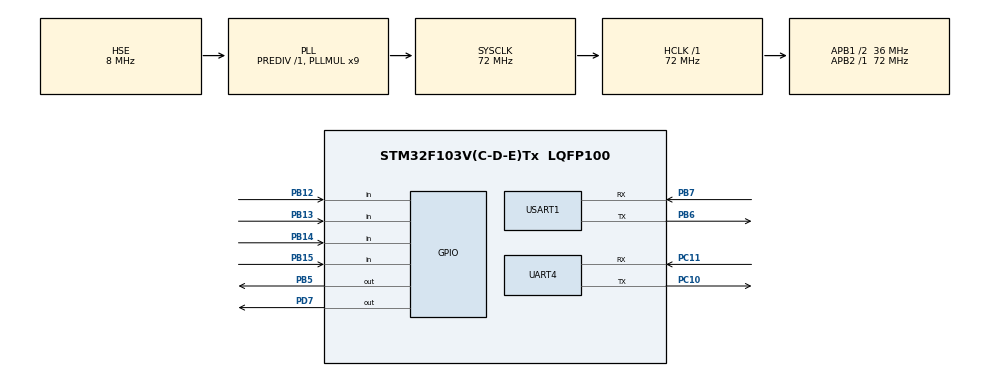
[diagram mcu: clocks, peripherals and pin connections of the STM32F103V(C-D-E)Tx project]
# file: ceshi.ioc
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Dma.Request0=USART1_RX
Dma.Request1=UART4_RX
Dma.UART4_RX.1.Direction=DMA_PERIPH_TO_MEMORY
Dma.UART4_RX.1.Instance=DMA2_Channel3
Dma.UART4_RX.1.MemDataAlignment=DMA_MDATAALIGN_BYTE
Dma.UART4_RX.1.MemInc=DMA_MINC_ENABLE
Dma.UART4_RX.1.Mode=DMA_NORMAL
Dma.UART4_RX.1.PeriphDataAlignment=DMA_PDATAALIGN_BYTE
Dma.UART4_RX.1.PeriphInc=DMA_PINC_DISABLE
Dma.UART4_RX.1.Priority=DMA_PRIORITY_LOW
Dma.USART1_RX.0.Direction=DMA_PERIPH_TO_MEMORY
Dma.USART1_RX.0.Instance=DMA1_Channel5
Dma.USART1_RX.0.MemDataAlignment=DMA_MDATAALIGN_BYTE
Dma.USART1_RX.0.MemInc=DMA_MINC_ENABLE
Dma.USART1_RX.0.Mode=DMA_NORMAL
Dma.USART1_RX.0.PeriphDataAlignment=DMA_PDATAALIGN_BYTE
Dma.USART1_RX.0.PeriphInc=DMA_PINC_DISABLE
Dma.USART1_RX.0.Priority=DMA_PRIORITY_LOW
Mcu.Family=STM32F1
Mcu.Name=STM32F103V(C-D-E)Tx
Mcu.Package=LQFP100
NVIC.DMA1_Channel5_IRQn=true\:2\:1\:true\:false\:true\:false
NVIC.DMA2_Channel3_IRQn=true\:2\:2\:true\:false\:true\:false
NVIC.PriorityGroup=NVIC_PRIORITYGROUP_2
NVIC.RCC_IRQn=true\:0\:0\:false\:false\:true\:true
NVIC.TIM6_IRQn=true\:1\:2\:true\:false\:true\:true
NVIC.TIM7_IRQn=true\:1\:1\:true\:false\:true\:true
NVIC.UART4_IRQn=true\:3\:3\:true\:false\:true\:true
NVIC.USART1_IRQn=true\:3\:2\:true\:false\:true\:true
OSC_IN.Mode=HSE-External-Oscillator
OSC_IN.Signal=RCC_OSC_IN
OSC_OUT.Mode=HSE-External-Oscillator
OSC_OUT.Signal=RCC_OSC_OUT
PB12.Signal=GPIO_Input
PB13.Signal=GPIO_Input
PB14.Signal=GPIO_Input
PB15.Signal=GPIO_Input
PB5.Signal=GPIO_Output
PB6.Mode=Asynchronous
PB6.Signal=USART1_TX
PB7.Mode=Asynchronous
PB7.Signal=USART1_RX
PC10.Mode=Asynchronous
PC10.Signal=UART4_TX
PC11.Mode=Asynchronous
PC11.Signal=UART4_RX
PD7.Signal=GPIO_Output
ProjectManager.HeapSize=0x200
ProjectManager.StackSize=0x400
ProjectManager.TargetToolchain=EWARM
RCC.AHBFreq_Value=72000000
RCC.APB1CLKDivider=RCC_HCLK_DIV2
RCC.APB1Freq_Value=36000000
RCC.APB1TimFreq_Value=72000000
RCC.APB2Freq_Value=72000000
RCC.APB2TimFreq_Value=72000000
RCC.HCLKFreq_Value=72000000
RCC.PLLMUL=RCC_PLL_MUL9
RCC.PLLSourceVirtual=RCC_PLLSOURCE_HSE
RCC.SYSCLKFreq_VALUE=72000000
RCC.SYSCLKSource=RCC_SYSCLKSOURCE_PLLCLK
RCC.USBFreq_Value=72000000
UART4.Parity=PARITY_EVEN
UART4.VirtualMode=Asynchronous
UART4.WordLength=WORDLENGTH_9B
USART1.Parity=PARITY_EVEN
USART1.VirtualMode=VM_ASYNC
USART1.WordLength=WORDLENGTH_9B
VP_SYS_VS_ND.Mode=No_Debug
VP_TIM6_VS_ClockSourceINT.Mode=Enable_Timer
VP_TIM7_VS_ClockSourceINT.Mode=Enable_Timer
board=custom

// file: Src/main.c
/**
  ******************************************************************************
//划分一页来记录表的地址与表的波特率 默认波特率为
//
//对待使用规约中广播地址的问题先用2400波特率发送一遍然后再用1200波特率发送一遍
//寻找DLT645-07的表中使用的部分
//定时器中断的开启关闭，是用完成必须关闭。系统时钟的定时器开启
******************************************************************************
  */
#include "main.h"
#include "stm32f1xx_hal.h"
#include "app.h"

TIM_HandleTypeDef htim6;
TIM_HandleTypeDef htim7;

UART_HandleTypeDef huart4;
UART_HandleTypeDef huart1;
DMA_HandleTypeDef hdma_uart4_rx;
DMA_HandleTypeDef hdma_usart1_rx;

/* USER CODE BEGIN PV */
/* Private variables ---------------------------------------------------------*/

/* USER CODE END PV */

void SystemClock_Config(void);
static void MX_GPIO_Init(void);
static void MX_DMA_Init(void);
static void MX_TIM6_Init(void);
static void MX_TIM7_Init(void);
static void MX_UART4_Init(void);
static void MX_USART1_UART_Init(void);

/* USER CODE BEGIN PFP */
/* Private function prototypes -----------------------------------------------*/

/* USER CODE END PFP */

/* USER CODE BEGIN 0 */
// 初始化波特率状态
/* USER CODE END 0 */
//灯的不同状态
uint8_t led_flag;

int main(void)
{

  /* MCU Configuration----------------------------------------------------------*/

  /* Reset of all peripherals, Initializes the Flash interface and the Systick. */
  HAL_Init();

  /* Configure the system clock */
  SystemClock_Config();

  /* Initialize all configured peripherals */
  MX_GPIO_Init();
  MX_DMA_Init();
  MX_TIM6_Init();
  MX_TIM7_Init();
  MX_UART4_Init();
  MX_USART1_UART_Init();
  RS_485_RX();

  init();

  /* Infinite loop */
  led_flag=1;
  /* USER CODE BEGIN WHILE */
  while (1)
  {
   process_cmd_tx_rx();
  }
  /* USER CODE END WHILE */

 }
void HAL_SYSTICK_Callback()
{
  uint32_t tickStart = HAL_GetTick();
  if(led_flag==1)
  {

    if(tickStart%100==0)
    HAL_GPIO_TogglePin(LED1_PORT,LED1_PIN);
  }
  else if(led_flag==2)
  {
   if(tickStart%1000==0)
    HAL_GPIO_TogglePin(LED1_PORT,LED1_PIN);
  }
   else if(led_flag==3)
  {
     if(tickStart%1000==0)
    HAL_GPIO_TogglePin(LED1_PORT,LED1_PIN);
  }

 }

void SystemClock_Config(void)
{

  RCC_OscInitTypeDef RCC_OscInitStruct;
  RCC_ClkInitTypeDef RCC_ClkInitStruct;

    /**Initializes the CPU, AHB and APB busses clocks
    */
  RCC_OscInitStruct.OscillatorType = RCC_OSCILLATORTYPE_HSE;
  RCC_OscInitStruct.HSEState = RCC_HSE_ON;
  RCC_OscInitStruct.HSEPredivValue = RCC_HSE_PREDIV_DIV1;
  RCC_OscInitStruct.HSIState = RCC_HSI_ON;
  RCC_OscInitStruct.PLL.PLLState = RCC_PLL_ON;
  RCC_OscInitStruct.PLL.PLLSource = RCC_PLLSOURCE_HSE;
  RCC_OscInitStruct.PLL.PLLMUL = RCC_PLL_MUL9;
  if (HAL_RCC_OscConfig(&RCC_OscInitStruct) != HAL_OK)
  {
    _Error_Handler(__FILE__, __LINE__);
  }

    /**Initializes the CPU, AHB and APB busses clocks
    */
  RCC_ClkInitStruct.ClockType = RCC_CLOCKTYPE_HCLK|RCC_CLOCKTYPE_SYSCLK
                              |RCC_CLOCKTYPE_PCLK1|RCC_CLOCKTYPE_PCLK2;
  RCC_ClkInitStruct.SYSCLKSource = RCC_SYSCLKSOURCE_PLLCLK;
  RCC_ClkInitStruct.AHBCLKDivider = RCC_SYSCLK_DIV1;
  RCC_ClkInitStruct.APB1CLKDivider = RCC_HCLK_DIV2;
  RCC_ClkInitStruct.APB2CLKDivider = RCC_HCLK_DIV1;

  if (HAL_RCC_ClockConfig(&RCC_ClkInitStruct, FLASH_LATENCY_2) != HAL_OK)
  {
    _Error_Handler(__FILE__, __LINE__);
  }

    /**Configure the Systick interrupt time
    */
  HAL_SYSTICK_Config(HAL_RCC_GetHCLKFreq()/1000);

    /**Configure the Systick
    */
  HAL_SYSTICK_CLKSourceConfig(SYSTICK_CLKSOURCE_HCLK);

  /* SysTick_IRQn interrupt configuration */
  HAL_NVIC_SetPriority(SysTick_IRQn, 0, 0);
}

/* TIM6 init function */
static void MX_TIM6_Init(void)
{

  TIM_MasterConfigTypeDef sMasterConfig;

  htim6.Instance = TIM6;
  htim6.Init.Prescaler = 71;
  htim6.Init.CounterMode = TIM_COUNTERMODE_UP;
  htim6.Init.Period = 999;
  htim6.Init.AutoReloadPreload = TIM_AUTORELOAD_PRELOAD_DISABLE;
  if (HAL_TIM_Base_Init(&htim6) != HAL_OK)
  {
    _Error_Handler(__FILE__, __LINE__);
  }

  sMasterConfig.MasterOutputTrigger = TIM_TRGO_RESET;
  sMasterConfig.MasterSlaveMode = TIM_MASTERSLAVEMODE_DISABLE;
  if (HAL_TIMEx_MasterConfigSynchronization(&htim6, &sMasterConfig) != HAL_OK)
  {
    _Error_Handler(__FILE__, __LINE__);
  }

}

/* TIM7 init function */
static void MX_TIM7_Init(void)
{

  TIM_MasterConfigTypeDef sMasterConfig;

  htim7.Instance = TIM7;
  htim7.Init.Prescaler = 360-1;;
  htim7.Init.CounterMode = TIM_COUNTERMODE_UP;
  htim7.Init.Period = 999;
  htim7.Init.AutoReloadPreload = TIM_AUTORELOAD_PRELOAD_DISABLE;
  if (HAL_TIM_Base_Init(&htim7) != HAL_OK)
  {
    _Error_Handler(__FILE__, __LINE__);
  }

  sMasterConfig.MasterOutputTrigger = TIM_TRGO_RESET;
  sMasterConfig.MasterSlaveMode = TIM_MASTERSLAVEMODE_DISABLE;
  if (HAL_TIMEx_MasterConfigSynchronization(&htim7, &sMasterConfig) != HAL_OK)
  {
    _Error_Handler(__FILE__, __LINE__);
  }

}

/* UART4 init function */
static void MX_UART4_Init(void)
{

  huart4.Instance = UART4;
  huart4.Init.BaudRate = 9600;
  huart4.Init.WordLength = UART_WORDLENGTH_9B;
  huart4.Init.StopBits = UART_STOPBITS_1;
  huart4.Init.Parity = UART_PARITY_EVEN;
  huart4.Init.Mode = UART_MODE_TX_RX;
  huart4.Init.HwFlowCtl = UART_HWCONTROL_NONE;
  huart4.Init.OverSampling = UART_OVERSAMPLING_16;
  if (HAL_UART_Init(&huart4) != HAL_OK)
  {
    _Error_Handler(__FILE__, __LINE__);
  }

}

/* USART1 init function */
static void MX_USART1_UART_Init(void)
{

  huart1.Instance = USART1;
  huart1.Init.BaudRate = 1200;
  huart1.Init.WordLength = UART_WORDLENGTH_9B;
  huart1.Init.StopBits = UART_STOPBITS_1;
  huart1.Init.Parity = UART_PARITY_EVEN;
  huart1.Init.Mode = UART_MODE_TX_RX;
  huart1.Init.HwFlowCtl = UART_HWCONTROL_NONE;
  huart1.Init.OverSampling = UART_OVERSAMPLING_16;
  if (HAL_UART_Init(&huart1) != HAL_OK)
  {
    _Error_Handler(__FILE__, __LINE__);
  }

}

static void MX_DMA_Init(void)
{
  /* DMA controller clock enable */
  __HAL_RCC_DMA1_CLK_ENABLE();
  __HAL_RCC_DMA2_CLK_ENABLE();

  /* DMA interrupt init */
  /* DMA1_Channel5_IRQn interrupt configuration */
  HAL_NVIC_SetPriority(DMA1_Channel5_IRQn, 2, 2);
  HAL_NVIC_EnableIRQ(DMA1_Channel5_IRQn);
  /* DMA2_Channel3_IRQn interrupt configuration */
  HAL_NVIC_SetPriority(DMA2_Channel3_IRQn, 2, 1);
  HAL_NVIC_EnableIRQ(DMA2_Channel3_IRQn);

}

/** Configure pins as
        * Analog
        * Input
        * Output
        * EVENT_OUT
        * EXTI
*/
static void MX_GPIO_Init(void)
{

  GPIO_InitTypeDef GPIO_InitStruct;

  /* GPIO Ports Clock Enable */
  __HAL_RCC_GPIOB_CLK_ENABLE();
  __HAL_RCC_GPIOC_CLK_ENABLE();
  __HAL_RCC_GPIOD_CLK_ENABLE();
  __HAL_RCC_GPIOE_CLK_ENABLE();

  /*Configure GPIO pin Output Level */
  HAL_GPIO_WritePin(GPIOD, GPIO_PIN_7, GPIO_PIN_RESET);

  /*Configure GPIO pin Output Level */
  HAL_GPIO_WritePin(GPIOB, GPIO_PIN_5, GPIO_PIN_RESET);

  HAL_GPIO_WritePin(GPIOB, GPIO_PIN_1, GPIO_PIN_RESET);

  HAL_GPIO_WritePin(GPIOE, GPIO_PIN_5, GPIO_PIN_RESET);
  /*Configure GPIO pins : PB12 PB13 PB14 PB15 */
  GPIO_InitStruct.Pin = GPIO_PIN_12|GPIO_PIN_13|GPIO_PIN_14|GPIO_PIN_15;
  GPIO_InitStruct.Mode = GPIO_MODE_INPUT;
  GPIO_InitStruct.Pull = GPIO_NOPULL;
  HAL_GPIO_Init(GPIOB, &GPIO_InitStruct);

  /*Configure GPIO pin : PD7 */
  GPIO_InitStruct.Pin = GPIO_PIN_7;
  GPIO_InitStruct.Mode = GPIO_MODE_OUTPUT_PP;
  GPIO_InitStruct.Pull = GPIO_NOPULL;
  GPIO_InitStruct.Speed = GPIO_SPEED_FREQ_LOW;
  HAL_GPIO_Init(GPIOD, &GPIO_InitStruct);

  /*Configure GPIO pin : PB5 */
  GPIO_InitStruct.Pin = GPIO_PIN_5|GPIO_PIN_1;
  GPIO_InitStruct.Mode = GPIO_MODE_OUTPUT_PP;
  GPIO_InitStruct.Pull = GPIO_NOPULL;
  GPIO_InitStruct.Speed = GPIO_SPEED_FREQ_LOW;
  HAL_GPIO_Init(GPIOB, &GPIO_InitStruct);

    /*Configure GPIO pin : PE5 */
  GPIO_InitStruct.Pin = GPIO_PIN_5;
  GPIO_InitStruct.Mode = GPIO_MODE_OUTPUT_PP;
  GPIO_InitStruct.Pull = GPIO_NOPULL;
  GPIO_InitStruct.Speed = GPIO_SPEED_FREQ_LOW;
  HAL_GPIO_Init(GPIOE, &GPIO_InitStruct);

}

void _Error_Handler(char *file, int line)
{
  while(1)
  {
  }
}

//     if(init_state)
//     {
//        if (set_init_buadrate()) //ccdebug
//            init_state=false;
//
//        if(timers>6)
//        {
//            init_state=false;
//            timers=0;
//        }
//        timers++;
//     }/* USER CODE END WHI*/
//    else

/************************ (C) COPYRIGHT STMicroelectronics *****END OF FILE****/
